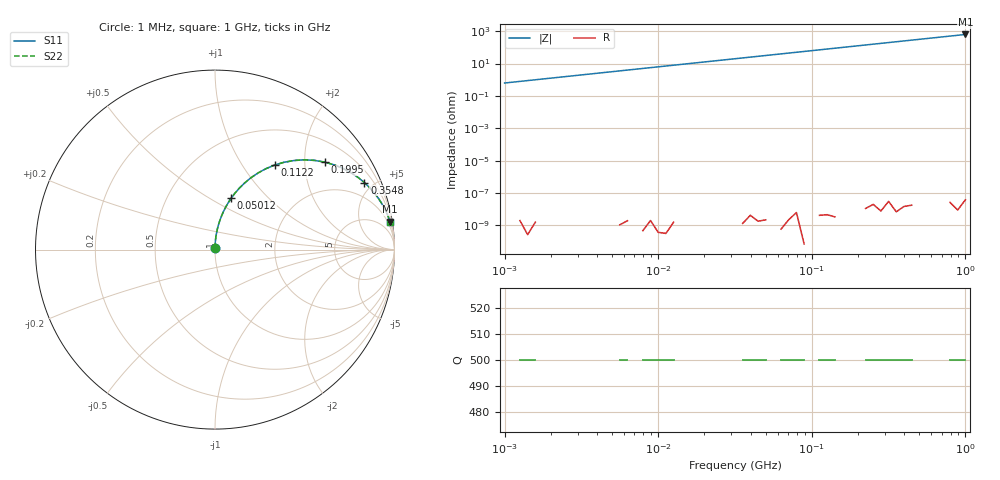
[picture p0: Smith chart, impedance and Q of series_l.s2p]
! s2psee demo: series 100 nH between 50 ohm ports
# HZ S RI R 50
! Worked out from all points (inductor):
!   61 points, 1 MHz to 1 GHz, reference 50 ohm
!   read as one part in series: L = 100 nH near 1 MHz
!   highest |Z| = 628 ohm at 1 GHz (marker M1)
!   S11 on the Smith chart (normalised r, x): 1 MHz: 1.00, +0.01; 50.12 MHz: 1.00, +0.63; 112.2 MHz: 1.00, +1.41; 199.5 MHz: 1.00, +2.51; 354.8 MHz: 1.00, +4.46; 1 GHz: 1, +13
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1000000  3.95e-05 0.00628  1 -0.00628  1 -0.00628  3.95e-05 0.00628
3548134  0.000497 0.0223  0.9995 -0.0223  0.9995 -0.0223  0.000497 0.0223
6309573  0.00157 0.0396  0.9984 -0.0396  0.9984 -0.0396  0.00157 0.0396
1e7  0.00393 0.0626  0.9961 -0.0626  0.9961 -0.0626  0.00393 0.0626
1.412538e7  0.00782 0.0881  0.9922 -0.0881  0.9922 -0.0881  0.00782 0.0881
1.995262e7  0.0155 0.1234  0.9845 -0.1234  0.9845 -0.1234  0.0155 0.1234
2.818383e7  0.0304 0.1717  0.9696 -0.1717  0.9696 -0.1717  0.0304 0.1717
3.548134e7  0.0473 0.2124  0.9527 -0.2124  0.9527 -0.2124  0.0473 0.2124
5.011872e7  0.0902 0.2865  0.9098 -0.2865  0.9098 -0.2865  0.0902 0.2865
6.309573e7  0.1358 0.3426  0.8642 -0.3426  0.8642 -0.3426  0.1358 0.3426
7.943282e7  0.1994 0.3996  0.8006 -0.3996  0.8006 -0.3996  0.1994 0.3996
8.912509e7  0.2387 0.4263  0.7613 -0.4263  0.7613 -0.4263  0.2387 0.4263
1.122018e8  0.332 0.4709  0.668 -0.4709  0.668 -0.4709  0.332 0.4709
1.412538e8  0.4406 0.4965  0.5594 -0.4965  0.5594 -0.4965  0.4406 0.4965
1.584893e8  0.4979 0.5  0.5021 -0.5  0.5021 -0.5  0.4979 0.5
1.995262e8  0.6111 0.4875  0.3889 -0.4875  0.3889 -0.4875  0.6111 0.4875
2.818383e8  0.7582 0.4282  0.2418 -0.4282  0.2418 -0.4282  0.7582 0.4282
3.548134e8  0.8325 0.3734  0.1675 -0.3734  0.1675 -0.3734  0.8325 0.3734
4.466836e8  0.8873 0.3162  0.1127 -0.3162  0.1127 -0.3162  0.8873 0.3162
5.623413e8  0.9258 0.262  0.0742 -0.262  0.0742 -0.262  0.9258 0.262
7.079458e8  0.9519 0.214  0.0481 -0.214  0.0481 -0.214  0.9519 0.214
1e9  0.9753 0.1552  0.0247 -0.1552  0.0247 -0.1552  0.9753 0.1552
